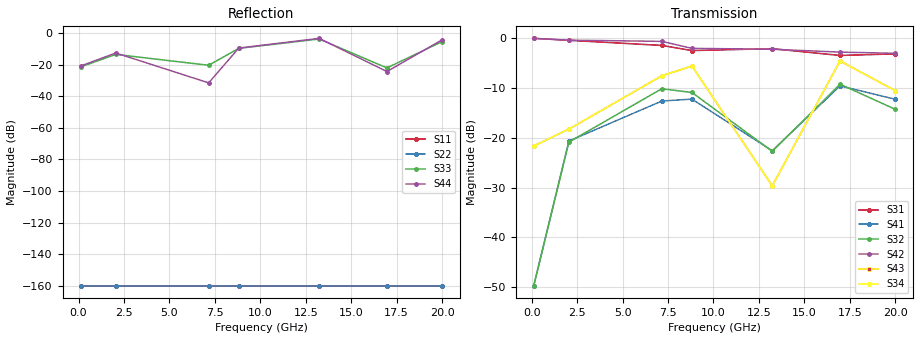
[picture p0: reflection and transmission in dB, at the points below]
! Touchstone generated by fitter/viewer
# HZ S  RI R 5.000000e+01
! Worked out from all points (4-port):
!   145 points, 112.2 MHz to 20 GHz, reference 50 ohm
!   strongest paths, dB at 112.2 MHz, 5.084 GHz, 10.06 GHz, 15.03 GHz, 20 GHz:
!     S42: 0.0, -0.5, -2.9, -2.6, -3.0
!     S31: 0.0, -0.5, -3.2, -3.2, -3.1
!     S43: -21.6, -17.8, -7.3, -8.1, -10.5
!     S32: -49.7, -21.1, -12.3, -10.5, -14.3
!     S41: -49.7, -19.7, -14.4, -11.8, -12.2
!     S21: -, -, -, -, -
!   lowest |S11| = - dB at 112.2 MHz (marker M1), VSWR 1.00, Z = 50 + j0 ohm
!   |S11| at or under -10 dB: start of sweep to end of sweep
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1.122018e8  -0 -0  -0 -0  -0 -0  -0 -0
            -0 -0  -0 -0  -0 -0  -0 -0
            0.9968 -0.0353  -7.4e-05 -0.00328  0.0834 -0.0179  0.0829 -0.00348
            -8.24e-05 -0.00328  0.9967 -0.0361  0.0829 -0.00348  0.0894 -0.0185
2.045738e9  -0 -0  -0 -0  -0 -0  -0 -0
            -0 -0  -0 -0  -0 -0  -0 -0
            0.7685 -0.5646  -0.0663 -0.0618  -0.1601 0.1397  0.0743 0.0972
            -0.0681 -0.0631  0.7599 -0.5819  0.0743 0.0972  -0.1741 0.1587
7.155797e9  -0 -0  -0 -0  -0 -0  -0 -0
            -0 -0  -0 -0  -0 -0  -0 -0
            -0.4495 -0.7182  -0.1918 0.245  -0.0627 0.0729  0.0534 0.4161
            -0.1165 0.2031  -0.5408 -0.7574  0.0534 0.4161  0.0264 0.00373
8.813114e9  -0 -0  -0 -0  -0 -0  -0 -0
            -0 -0  -0 -0  -0 -0  -0 -0
            -0.6117 -0.4381  0.0947 0.2695  0.0857 0.3195  0.514 0.1165
            0.0882 0.2286  -0.7033 -0.3636  0.514 0.1165  0.1535 0.301
1.323262e10  -0 -0  -0 -0  -0 -0  -0 -0
             -0 -0  -0 -0  -0 -0  -0 -0
             -0.7387 0.2672  0.0187 0.0709  0.4716 -0.4533  -0.0327 -0.00453
             0.0521 0.0529  -0.6899 0.3543  -0.0327 -0.00453  0.4602 -0.5074
1.696159e10  -0 -0  -0 -0  -0 -0  -0 -0
             -0 -0  -0 -0  -0 -0  -0 -0
             -0.1701 0.65  0.2614 -0.2258  0.0413 -0.0678  0.5339 -0.2553
             0.2382 -0.2324  -0.0172 0.7258  0.5339 -0.2553  0.0518 -0.0321
2e10  -0 -0  -0 -0  -0 -0  -0 -0
      -0 -0  -0 -0  -0 -0  -0 -0
      0.388 0.5789  -0.0772 -0.1776  0.3563 -0.4071  -0.1993 -0.2217
      -0.128 -0.2078  0.5125 0.486  -0.1993 -0.2217  0.329 -0.5216
